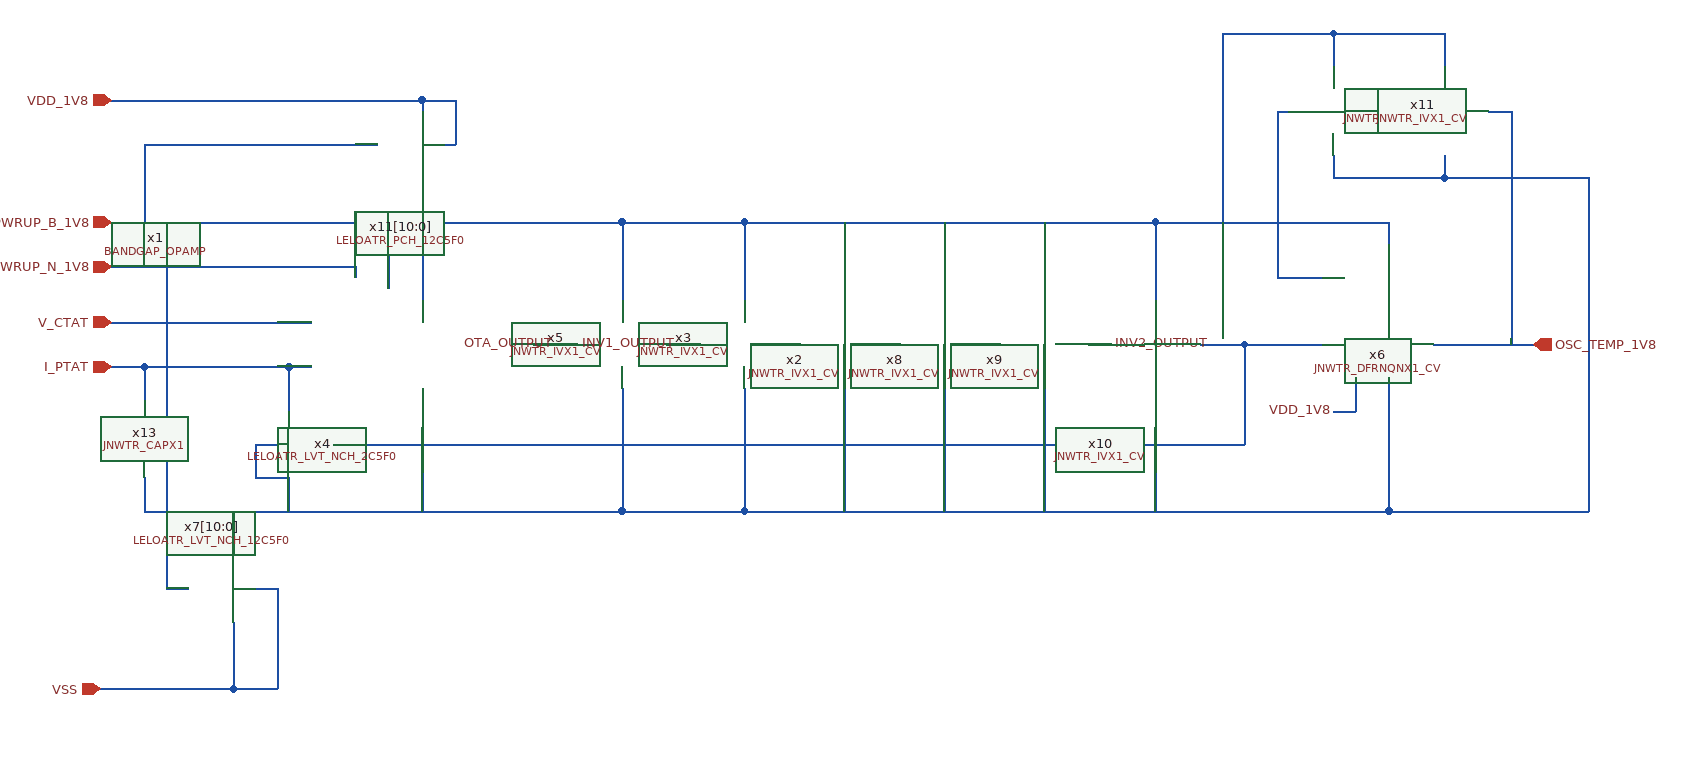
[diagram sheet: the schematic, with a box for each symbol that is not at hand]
v {xschem version=3.4.7 file_version=1.2}
G {}
K {}
V {}
S {}
E {}
N -70 150 100 150 {lab=#net1}
N -70 20 -40 20 {lab=I_PTAT}
N 350 0 380 0 {lab=INV1_OUTPUT}
N 310 40 310 110 {lab=#net1}
N 100 150 310 150 {lab=#net1}
N 310 150 420 150 {lab=#net1}
N 420 40 420 110 {lab=#net1}
N 310 -100 310 -40 {lab=#net2}
N 310 -110 310 -100 {lab=#net2}
N 310 -110 420 -110 {lab=#net2}
N 420 -110 420 -40 {lab=#net2}
N 420 110 420 150 {lab=#net1}
N 310 110 310 150 {lab=#net1}
N -120 20 -70 20 {lab=I_PTAT}
N -150 -20 -70 -20 {lab=V_CTAT}
N 10 120 10 150 {lab=#net1}
N -20 90 10 90 {lab=#net1}
N -20 90 -20 120 {lab=#net1}
N 10 20 10 60 {lab=I_PTAT}
N 840 90 870 90 {lab=INV2_OUTPUT}
N 870 0 870 90 {lab=INV2_OUTPUT}
N 870 0 940 0 {lab=INV2_OUTPUT}
N 1000 30 1000 150 {lab=#net1}
N 420 150 640 150 {lab=#net1}
N 900 -60 940 -60 {lab=#net3}
N 130 -60 130 -40 {lab=#net2}
N 970 30 970 60 {lab=VDD_1V8}
N 1110 -130 1110 0 {lab=OSC_TEMP_1V8}
N 900 -130 900 -60 {lab=#net3}
N -120 20 -120 50 {lab=I_PTAT}
N -120 120 -120 150 {lab=#net1}
N -150 20 -120 20 {lab=I_PTAT}
N -40 20 10 20 {lab=I_PTAT}
N -20 120 10 120 {lab=#net1}
N 250 0 270 0 {lab=OTA_OUTPUT}
N 230 0 250 -0 {lab=OTA_OUTPUT}
N 50 90 480 90 {lab=INV2_OUTPUT}
N 840 0 870 -0 {lab=INV2_OUTPUT}
N 730 -0 750 0 {lab=#net4}
N 640 0 650 0 {lab=#net5}
N 550 -0 560 -0 {lab=#net6}
N 460 -0 470 -0 {lab=#net7}
N 480 90 840 90 {lab=INV2_OUTPUT}
N 420 -110 790 -110 {lab=#net2}
N 790 -110 790 -40 {lab=#net2}
N 690 -110 690 -40 {lab=#net2}
N 600 -110 600 -40 {lab=#net2}
N 510 -110 510 -40 {lab=#net2}
N 640 150 1000 150 {lab=#net1}
N 510 40 510 150 {lab=#net1}
N 600 40 600 150 {lab=#net1}
N 690 40 690 140 {lab=#net1}
N 690 140 690 150 {lab=#net1}
N 790 40 790 150 {lab=#net1}
N 830 -0 840 -0 {lab=INV2_OUTPUT}
N -70 -20 30 -20 {lab=V_CTAT}
N 10 20 30 20 {lab=I_PTAT}
N 130 40 130 150 {lab=#net1}
N 130 -110 130 -60 {lab=#net2}
N 70 -70 70 -60 {lab=PWRUP_N_1V8}
N -150 -70 70 -70 {lab=PWRUP_N_1V8}
N 100 -110 100 -50 {lab=PWRUP_B_1V8}
N -150 -110 100 -110 {lab=PWRUP_B_1V8}
N 130 -150 130 -110 {lab=#net2}
N 130 -110 310 -110 {lab=#net2}
N 950 60 970 60 {lab=VDD_1V8}
N 790 -110 1000 -110 {lab=#net2}
N 1000 -110 1000 -90 {lab=#net2}
N -120 150 -70 150 {lab=#net1}
N -100 220 -80 220 {lab=PWRUP_B_1V8}
N -40 150 -40 190 {lab=#net1}
N -40 250 -40 310 {lab=VSS}
N -160 310 -40 310 {lab=VSS}
N -40 220 -0 220 {lab=VSS}
N -0 220 0 310 {lab=VSS}
N -40 310 -0 310 {lab=VSS}
N -100 -110 -100 220 {lab=PWRUP_B_1V8}
N -150 -220 130 -220 {lab=VDD_1V8}
N 130 -220 130 -210 {lab=VDD_1V8}
N -120 -180 90 -180 {lab=PWRUP_N_1V8}
N 130 -180 160 -180 {lab=VDD_1V8}
N 160 -220 160 -180 {lab=VDD_1V8}
N 130 -220 160 -220 {lab=VDD_1V8}
N -120 -180 -120 -70 {lab=PWRUP_N_1V8}
N 900 -210 900 -130 {lab=#net3}
N 1090 -210 1110 -210 {lab=OSC_TEMP_1V8}
N 1110 -210 1110 -130 {lab=OSC_TEMP_1V8}
N 900 -210 910 -210 {lab=#net3}
N 850 -250 850 -110 {lab=#net2}
N 1180 140 1180 150 {lab=#net1}
N 1000 150 1180 150 {lab=#net1}
N 850 -280 850 -250 {lab=#net2}
N 850 -280 950 -280 {lab=#net2}
N 950 -280 950 -250 {lab=#net2}
N 950 -280 1050 -280 {lab=#net2}
N 1050 -280 1050 -250 {lab=#net2}
N 950 -170 950 -150 {lab=#net1}
N 950 -150 1050 -150 {lab=#net1}
N 1050 -170 1050 -150 {lab=#net1}
N 1050 -170 1050 -150 {lab=#net1}
N 1050 -150 1180 -150 {lab=#net1}
N 990 -210 1010 -210 {lab=#net8}
N 1040 0 1130 0 {lab=OSC_TEMP_1V8}
N 1180 -150 1180 140 {lab=#net1}
C {devices/ipin.sym} -150 -110 0 0 {name=p1 lab=PWRUP_B_1V8}
C {devices/opin.sym} 1130 0 0 0 {name=p2 lab=OSC_TEMP_1V8}
C {devices/ipin.sym} -150 -70 0 0 {name=p3 lab=PWRUP_N_1V8}
C {devices/ipin.sym} -150 -220 0 0 {name=p4 lab=VDD_1V8}
C {devices/ipin.sym} -160 310 0 0 {name=p5 lab=VSS}
C {devices/ipin.sym} -150 -20 0 0 {name=p6 lab=V_CTAT}
C {devices/ipin.sym} -150 20 0 0 {name=p7 lab=I_PTAT}
C {JNW_TR_SKY130A/JNWTR_IVX1_CV.sym} 270 0 0 0 {name=x5 }
C {JNW_TR_SKY130A/JNWTR_IVX1_CV.sym} 380 0 0 0 {name=x3 }
C {JNW_TR_SKY130A/JNWTR_DFRNQNX1_CV.sym} 940 0 0 0 {name=x6 }
C {devices/lab_wire.sym} 950 60 0 0 {name=p11 sig_type=std_logic lab=VDD_1V8}
C {devices/lab_wire.sym} 250 0 1 0 {name=p8 sig_type=std_logic lab=OTA_OUTPUT}
C {devices/lab_wire.sym} 360 0 1 0 {name=p9 sig_type=std_logic lab=INV1_OUTPUT}
C {devices/lab_wire.sym} 840 0 1 0 {name=p12 sig_type=std_logic lab=INV2_OUTPUT}
C {LELO_ATR_SKY130A/LELOATR_LVT_NCH_2C5F0.sym} 50 90 0 1 {name=x4 }
C {LELO_GR02_SKY130A/BANDGAP_OPAMP.sym} -60 -90 1 0 {name=x1}
C {JNW_TR_SKY130A/JNWTR_IVX1_CV.sym} 470 0 0 0 {name=x2 }
C {JNW_TR_SKY130A/JNWTR_IVX1_CV.sym} 560 0 0 0 {name=x8 }
C {JNW_TR_SKY130A/JNWTR_IVX1_CV.sym} 650 0 0 0 {name=x9 }
C {JNW_TR_SKY130A/JNWTR_IVX1_CV.sym} 750 0 0 0 {name=x10 }
C {JNW_TR_SKY130A/JNWTR_CAPX1.sym} -120 110 0 0 {name=x13 }
C {LELO_ATR_SKY130A/LELOATR_LVT_NCH_12C5F0.sym} -80 220 0 0 {name=x7[10:0]}
C {LELO_ATR_SKY130A/LELOATR_PCH_12C5F0.sym} 90 -180 0 0 {name=x11[10:0]}
C {JNW_TR_SKY130A/JNWTR_IVX1_CV.sym} 990 -210 0 1 {name=x7 }
C {JNW_TR_SKY130A/JNWTR_IVX1_CV.sym} 1090 -210 0 1 {name=x11 }
